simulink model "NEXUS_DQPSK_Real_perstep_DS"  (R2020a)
settings: Solver=VariableStepAuto  StartTime=0.0  StopTime=inf  RelTol=1e-3  EnableMultiTasking=on
InitFcn:
  | FrameSize = 32+1784+256;
  | SamplingTime = 1/(38.4e3)*2;
  | IQframeSize = (32+1784+256)/2;
  | %同期コードが必ず含まれるように32を足す
  | h_time = 1;
  | 
  | % General simulation parameters
  | M = 4;                         % M-PSK alphabet size
  | Upsampling = 4;            % Upsampling factor
  | Downsampling = 2;        % Downsampling factor
  | Fs = 2e6;                     % Sample rate
  | Ts = 1/Fs;                    % Sample time
  | %%FrameSize = 111;          % Number of modulated symbols per frame
  | %MessageLength = 105;  % Number of message bits per frame, 7 ASCII characters
  | BarkerLength = 13;        % Number of Barker code symbols
  | 
  | % TED
  | %fs = 2.4e6;
  | %fs = Fs/2;
  | fs = Fs;
  | Rdata = 100e3;
  | Rsymbol = Rdata/2;
  | 
  | % --- Early Late Timing Synchronisation ----
  | % synch loop design
  | d = 0.707;                   % damping ratio
  | 
  | %Ts = 1/Rsymbol;           % symbol period
  | Ks = 3.22;                    % phase detector coefficient
  | BnS = 0.1*Rsymbol;      % noise bandwidth in Hz
  | Kn   = 1;                      % gain of numerically controlled clock
  | 
  | % calculate loop filter coefficients
  | Ka = (4*d*BnS*Ts)/(Kn*Ks*(d+1/(4*d)));
  | Kb = (4*(BnS*Ts)^2)/(Kn*Ks*(d+1/4*d)^2);
  | 
  | temp=[-1+1i; -1i; -1-1i; -1; 1+1i; 1i; 1-1i; -1; 1+1i; -1i; -1+1i; -1; -1-1i; 1; -1-1i; 1];
  | DQPSKPreamble=temp./abs(temp);
  | PreambleDetectorThreshhold=20;
  | PreambleLength=16;
undefined symbols (not defined in the file or in its folder): Column, D, vector
libraries: dspindex x3, commrfcorlib x2, commsync2 x2, commdigbbndpm3 x1, commfilt2 x1

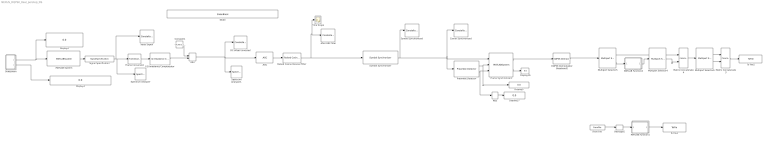
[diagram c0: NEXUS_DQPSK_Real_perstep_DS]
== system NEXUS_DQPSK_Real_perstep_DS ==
  AGC : commrfcorlib/AGC  LegacyMode=off  DetectorMethod=Rectifier  LoopMethod=Linear  UpdatePeriod=100  StepSize=0.1  AdaptationStepSize=0.1  DesiredOutputPower=0.3  AveragingLength=1000  MaximumGain=30  MaxPowerGain=50  GainOutputPort=off  InputPowerOutputPort=off  SimulateUsing=Interpreted execution
  Add : Sum
  After RRC filter : ConstellationDiagram  Commented=on
  Carrier Synchronized : ConstellationDiagram
  Constant1 : Constant  Value=-10.78e-3-10.00e-3j
  DC offset corrected : ConstellationDiagram  Commented=on
  DQPSK Demodulator Baseband2 : commdigbbndpm3/DQPSK Demodulator Baseband  OutType=Bit  Dec=Gray  Ph=pi/4  outDtype1=double  outDtype2=Inherit via internal rule
  Display{2,4..5,16..17} (5 alike) : Display
  Frame Conversion : FrameConversion
  Frame Synchronizer1 : MATLABSystem  System=comm.internal.examples.FrameSynchronizer  Input=Symbol  OutputFrameLength=IQframeSize  PreambleLength=PreambleLength  SimulateUsing=Code generation
  From File : FromFile  Commented=on  SampleTime=0
  I/Q Imbalance Compensator : commrfcorlib/I//Q Imbalance Compensator  Commented=through  CoefficientSource=Estimated from input signal  InitialCoefficient=0 + 0j  StepSizeSource=Property  StepSize=0.00001  AdaptInputPort=off  CoefficientOutputPort=off  SimulateUsing=Code generation
  Input Signal : ConstellationDiagram  Commented=on
  MATLAB Function1 : MATLAB Function  Commented=on  TreatAsAtomicUnit=on
  MATLAB Function4 : MATLAB Function  TreatAsAtomicUnit=on
  MATLAB System : MATLABSystem  System=bladeRF_Simulink_new2  loopback_mode=None  xb200=off  SimulateUsing=Interpreted execution  enable_rx=on  enable_overrun=off  rx_frequency=435.9e6  rx_samplerate=40/SamplingTime  rx_bandwidth=1.5  rx_gain=29  rx_agc=MANUAL  rx_num_buffers=1024  rx_num_transfers=16  rx_buf_size=524288  rx_timeout_ms=15000  rx_step_size=IQframeSize*40  enable_tx=off  enable_underrun=off  tx_frequency=920e6  tx_samplerate=3e6  tx_bandwidth=1.5  tx_gain=60  tx_num_buffers=64  tx_num_transfers=16  tx_buf_size=16384  tx_timeout_ms=5000  tx_step_size=16384  verbosity=Info
  Matrix Concatenate3 : Concatenate  Mode=Multidimensional array
  Matrix Concatenate4 : Concatenate  Mode=Multidimensional array
  Max : MinMax  Function=max
  Multiport Selector4 : dspindex/Multiport Selector  rowsOrCols=Rows  idxCellArray={[1:2040]}  idxErrMode=Clip Index
  Multiport Selector5 : dspindex/Multiport Selector  rowsOrCols=Rows  idxCellArray={[1:32],[33:2072]}  idxErrMode=Clip Index
  Multiport Selector6 : dspindex/Multiport Selector  rowsOrCols=Rows  idxCellArray={[1:1816],[1817:2072]}  idxErrMode=Clip Index
  Preamble Detector : commsync2/Preamble Detector  Input=Symbol  Preamble=DQPSKPreamble  Threshold=7.5  DetectionMetricOutput=on  Detections=First  SimulateUsing=Code generation
  Raised Cosine Receive Filter : commfilt2/Raised Cosine Receive Filter  filtType=Square root  R=0.5  filtSpan=20  N=40  downFactor=10  downOffset=0  filterGain=1/5  InputProcessing=Columns as channels (frame based)  RateOptions=Enforce single-rate processing  framing=Mute  checkCoeff=off  variableName=rcRxFilt  currentFiltSpan=20  D=(20)/2  inputOffset=0  sampMode=Mute  saveAsFlag=0  rateMode=Downsampling  checkGain=Normalized  launchFVT=on  roundingMode=Floor  overflowMode=off  coeffDataTypeStr=Inherit: Same word length as input  coeffMin=[]  coeffMax=[]  coeffLastDataTypeStr=Inherit: Same word length as input  accumDataTypeStr=Inherit: Same as product output  accumLastDataTypeStr=Inherit: Same as product output  outputDataTypeStr=Inherit: Same as accumulator  outputMin=[]  outputMax=[]  outputLastDataTypeStr=Inherit: Same as accumulator
  Reshape5 : Reshape  Commented=on  OutputDimensionality=Column vector (2-D)
  Signal Specification : SignalSpecification  SampleTime=(IQframeSize*400)/(400/SamplingTime)
  Slider : SliderBlock  ScaleMin=-1  ScaleMax=1  TickInterval=0.050000000000000003
  Spectrum Analyzer : SpectrumAnalyzer  Commented=on
  Spectrum Analyzer1 : SpectrumAnalyzer  Commented=on
  Subsystem : Subsystem
  Symbol Synchronized : ConstellationDiagram  Commented=on
  Symbol Synchronizer : commsync2/Symbol Synchronizer  Modulation=PAM/PSK/QAM  TimingErrorDetector=Gardner (non-data-aided)  SamplesPerSymbol=4  DampingFactor=0.86  NormalizedLoopBandwidth=0.0045  DetectorGain=2.7  TimingErrorOutputPort=off  SimulateUsing=Code generation
  Time Scope : Scope
  To File1 : ToFile  Commented=on  Filename=descramble_data
  To File2 : ToFile  Filename=C:\Users\Eve\Desktop\sample_code_Simulink\data_analysis\QPSK_decodedata.mat
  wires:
  Signal Specification/1 -> Spectrum Analyzer/1, Frame Conversion/1, Input Signal/1
  MATLAB System/1 -> Signal Specification/1
  Subsystem/2(Out2) -> Display4/1
  Subsystem/1(Out1) -> MATLAB System/1, Display2/1
  Raised Cosine Receive Filter/1 -> Symbol Synchronizer/1, Time Scope/1, After RRC filter/1
  I/Q Imbalance Compensator/1 -> Add/2
  AGC/1 -> Raised Cosine Receive Filter/1
  Frame Conversion/1 -> I/Q Imbalance Compensator/1
  Add/1 -> Spectrum Analyzer1/1, DC offset corrected/1, AGC/1
  Constant1/1 -> Add/1
  Multiport Selector4/1 -> Matrix Concatenate4/2
  Multiport Selector5/1 -> Matrix Concatenate4/1
  Matrix Concatenate3/1 -> To File2/1
  MATLAB Function4/1(y) -> Multiport Selector4/1
  Multiport Selector6/2 -> Matrix Concatenate3/2
  DQPSK Demodulator Baseband2/1 -> Multiport Selector5/1
  Multiport Selector5/2 -> MATLAB Function4/1(u)
  Matrix Concatenate4/1 -> Multiport Selector6/1
  Multiport Selector6/1 -> Matrix Concatenate3/1
  Max/1 -> Display17/1
  Preamble Detector/1 -> Frame Synchronizer1/2, Display5/1
  Frame Synchronizer1/1 -> DQPSK Demodulator Baseband2/1
  Symbol Synchronizer/1 -> Frame Synchronizer1/1, Carrier Synchronized/1, Preamble Detector/1, Symbol Synchronized/1
  Frame Synchronizer1/2 -> Display16/1
  Preamble Detector/2 -> Frame Synchronizer1/3, Max/1
  Reshape5/1 -> MATLAB Function1/1(u)
  MATLAB Function1/1(y) -> To File1/1
  From File/1 -> Reshape5/1

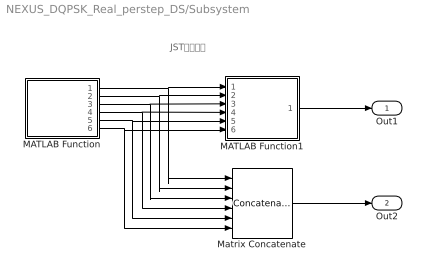
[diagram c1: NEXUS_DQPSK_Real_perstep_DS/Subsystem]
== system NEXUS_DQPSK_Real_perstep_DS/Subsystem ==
  note: JSTのみ対応
  MATLAB Function : MATLAB Function  TreatAsAtomicUnit=on
  MATLAB Function1 : MATLAB Function  TreatAsAtomicUnit=on
  Matrix Concatenate : Concatenate  Commented=on  NumInputs=6  Mode=Multidimensional array  ConcatenateDimension=2
  Out1 : Outport  VectorParamsAs1DForOutWhenUnconnected=off
  Out2 : Outport  Port=2  VectorParamsAs1DForOutWhenUnconnected=off
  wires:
  MATLAB Function/4(H) -> Matrix Concatenate/4, MATLAB Function1/4(H)
  MATLAB Function/3(D) -> Matrix Concatenate/3, MATLAB Function1/3(D)
  MATLAB Function/1(Y) -> Matrix Concatenate/1, MATLAB Function1/1(Y)
  MATLAB Function/5(MN) -> Matrix Concatenate/5, MATLAB Function1/5(MN)
  MATLAB Function/2(M) -> Matrix Concatenate/2, MATLAB Function1/2(M)
  MATLAB Function/6(S) -> Matrix Concatenate/6, MATLAB Function1/6(S)
  MATLAB Function1/1(data) -> Out1/1
  Matrix Concatenate/1 -> Out2/1

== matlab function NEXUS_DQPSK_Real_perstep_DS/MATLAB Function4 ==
function y = fcn(u)

randomiz = [1 1 1 1 1 1 1 1 0 1 0 0 1 0 0 0 0 0 0 0 1 1 1 0 1 1 0 0 0 0 0 0 1 0 0 1 1 0 1 0 0 0 0 0 1 1 0 1 0 1 1 1 0 0 0 0 1 0 1 1 1 1 0 0 1 0 0 0 1 1 1 0 0 0 1 0 1 1 0 0 1 0 0 1 0 0 1 1 1 0 1 0 1 1 0 1 1 0 1 0 0 1 1 1 1 0 1 1 0 1 1 1 0 1 0 0 0 1 1 0 1 1 0 0 1 1 1 0 0 1 0 1 1 0 1 0 1 0 0 1 0 1 1 1 0 1 1 1 1 1 0 1 1 1 0 0 1 1 0 0 0 0 1 1 0 0 1 0 1 0 1 0 0 0 1 0 1 0 1 1 1 1 1 1 0 0 1 1 1 1 1 0 0 0 0 0 1 0 1 0 0 0 0 1 0 0 0 0 1 1 1 1 0 0 0 1 1 0 0 0 1 0 0 0 1 0 0 1 0 1 0 0 1 1 0 0 1 1 0 1 1 1 1 0 1 0 1 0 1 0 1 1 0 0 0 1 1 1 1 1 1 1 1 0 1 0 0 1 0 0 0 0 0 0 0 1 1 1 0 1 1 0 0 0 0 0 0 1 0 0 1 1 0 1 0 0 0 0 0 1 1 0 1 0 1 1 1 0 0 0 0 1 0 1 1 1 1 0 0 1 0 0 0 1 1 1 0 0 0 1 0 1 1 0 0 1 0 0 1 0 0 1 1 1 0 1 0 1 1 0 1 1 0 1 0 0 1 1 1 1 0 1 1 0 1 1 1 0 1 0 0 0 1 1 0 1 1 0 0 1 1 1 0 0 1 0 1 1 0 1 0 1 0 0 1 0 1 1 1 0 1 1 1 1 1 0 1 1 1 0 0 1 1 0 0 0 0 1 1 0 0 1 0 1 0 1 0 0 0 1 0 1 0 1 1 1 1 1 1 0 0 1 1 1 1 1 0 0 0 0 0 1 0 1 0 0 0 0 1 0 0 0 0 1 1 1 1 0 0 0 1 1 0 0 0 1 0 0 0 1 0 0 1 0 1 0 0 1 1 0 0 1 1 0 1 1 1 1 0 1 0 1 0 1 0 1 1 0 0 0 1 1 1 1 1 1 1 1 0 1 0 0 1 0 0 0 0 0 0 0 1 1 1 0 1 1 0 0 0 0 0 0 1 0 0 1 1 0 1 0 0 0 0 0 1 1 0 1 0 1 1 1 0 0 0 0 1 0 1 1 1 1 0 0 1 0 0 0 1 1 1 0 0 0 1 0 1 1 0 0 1 0 0 1 0 0 1 1 1 0 1 0 1 1 0 1 1 0 1 0 0 1 1 1 1 0 1 1 0 1 1 1 0 1 0 0 0 1 1 0 1 1 0 0 1 1 1 0 0 1 0 1 1 0 1 0 1 0 0 1 0 1 1 1 0 1 1 1 1 1 0 1 1 1 0 0 1 1 0 0 0 0 1 1 0 0 1 0 1 0 1 0 0 0 1 0 1 0 1 1 1 1 1 1 0 0 1 1 1 1 1 0 0 0 0 0 1 0 1 0 0 0 0 1 0 0 0 0 1 1 1 1 0 0 0 1 1 0 0 0 1 0 0 0 1 0 0 1 0 1 0 0 1 1 0 0 1 1 0 1 1 1 1 0 1 0 1 0 1 0 1 1 0 0 0 1 1 1 1 1 1 1 1 0 1 0 0 1 0 0 0 0 0 0 0 1 1 1 0 1 1 0 0 0 0 0 0 1 0 0 1 1 0 1 0 0 0 0 0 1 1 0 1 0 1 1 1 0 0 0 0 1 0 1 1 1 1 0 0 1 0 0 0 1 1 1 0 0 0 1 0 1 1 0 0 1 0 0 1 0 0 1 1 1 0 1 0 1 1 0 1 1 0 1 0 0 1 1 1 1 0 1 1 0 1 1 1 0 1 0 0 0 1 1 0 1 1 0 0 1 1 1 0 0 1 0 1 1 0 1 0 1 0 0 1 0 1 1 1 0 1 1 1 1 1 0 1 1 1 0 0 1 1 0 0 0 0 1 1 0 0 1 0 1 0 1 0 0 0 1 0 1 0 1 1 1 1 1 1 0 0 1 1 1 1 1 0 0 0 0 0 1 0 1 0 0 0 0 1 0 0 0 0 1 1 1 1 0 0 0 1 1 0 0 0 1 0 0 0 1 0 0 1 0 1 0 0 1 1 0 0 1 1 0 1 1 1 1 0 1 0 1 0 1 0 1 1 0 0 0 1 1 1 1 1 1 1 1 0 1 0 0 1 0 0 0 0 0 0 0 1 1 1 0 1 1 0 0 0 0 0 0 1 0 0 1 1 0 1 0 0 0 0 0 1 1 0 1 0 1 1 1 0 0 0 0 1 0 1 1 1 1 0 0 1 0 0 0 1 1 1 0 0 0 1 0 1 1 0 0 1 0 0 1 0 0 1 1 1 0 1 0 1 1 0 1 1 0 1 0 0 1 1 1 1 0 1 1 0 1 1 1 0 1 0 0 0 1 1 0 1 1 0 0 1 1 1 0 0 1 0 1 1 0 1 0 1 0 0 1 0 1 1 1 0 1 1 1 1 1 0 1 1 1 0 0 1 1 0 0 0 0 1 1 0 0 1 0 1 0 1 0 0 0 1 0 1 0 1 1 1 1 1 1 0 0 1 1 1 1 1 0 0 0 0 0 1 0 1 0 0 0 0 1 0 0 0 0 1 1 1 1 0 0 0 1 1 0 0 0 1 0 0 0 1 0 0 1 0 1 0 0 1 1 0 0 1 1 0 1 1 1 1 0 1 0 1 0 1 0 1 1 0 0 0 1 1 1 1 1 1 1 1 0 1 0 0 1 0 0 0 0 0 0 0 1 1 1 0 1 1 0 0 0 0 0 0 1 0 0 1 1 0 1 0 0 0 0 0 1 1 0 1 0 1 1 1 0 0 0 0 1 0 1 1 1 1 0 0 1 0 0 0 1 1 1 0 0 0 1 0 1 1 0 0 1 0 0 1 0 0 1 1 1 0 1 0 1 1 0 1 1 0 1 0 0 1 1 1 1 0 1 1 0 1 1 1 0 1 0 0 0 1 1 0 1 1 0 0 1 1 1 0 0 1 0 1 1 0 1 0 1 0 0 1 0 1 1 1 0 1 1 1 1 1 0 1 1 1 0 0 1 1 0 0 0 0 1 1 0 0 1 0 1 0 1 0 0 0 1 0 1 0 1 1 1 1 1 1 0 0 1 1 1 1 1 0 0 0 0 0 1 0 1 0 0 0 0 1 0 0 0 0 1 1 1 1 0 0 0 1 1 0 0 0 1 0 0 0 1 0 0 1 0 1 0 0 1 1 0 0 1 1 0 1 1 1 1 0 1 0 1 0 1 0 1 1 0 0 0 1 1 1 1 1 1 1 1 0 1 0 0 1 0 0 0 0 0 0 0 1 1 1 0 1 1 0 0 0 0 0 0 1 0 0 1 1 0 1 0 0 0 0 0 1 1 0 1 0 1 1 1 0 0 0 0 1 0 1 1 1 1 0 0 1 0 0 0 1 1 1 0 0 0 1 0 1 1 0 0 1 0 0 1 0 0 1 1 1 0 1 0 1 1 0 1 1 0 1 0 0 1 1 1 1 0 1 1 0 1 1 1 0 1 0 0 0 1 1 0 1 1 0 0 1 1 1 0 0 1 0 1 1 0 1 0 1 0 0 1 0 1 1 1 0 1 1 1 1 1 0 1 1 1 0 0 1 1 0 0 0 0 1 1 0 0 1 0 1 0 1 0 0 0 1 0 1 0 1 1 1 1 1 1 0 0 1 1 1 1 1 0 0 0 0 0 1 0 1 0 0 0 0 1 0 0 0 0 1 1 1 1 0 0 0 1 1 0 0 0 1 0 0 0 1 0 0 1 0 1 0 0 1 1 0 0 1 1 0 1 1 1 1 0 1 0 1 0 1 0 1 1 0 0 0 1 1 1 1 1 1 1 1 0 1 0 0 1 0 0 0 0 0 0 0 1 1 1 0 1 1 0 0 0 0 0 0 1 0 0 1 1 0 1 0 0 0 0 0 1 1 0 1 0 1 1 1 0 0 0 0 1 0 1 1 1 1 0 0 1 0 0 0 1 1 1 0 0 0 1 0 1 1 0 0 1 0 0 1 0 0 1 1 1 0 1 0 1 1 0 1 1 0 1 0 0 1 1 1 1 0 1 1 0 1 1 1 0 1 0 0 0 1 1 0 1 1 0 0 1 1 1 0 0 1 0 1 1 0 1 0 1 0 0 1 0 1 1 1 0 1 1 1 1 1 0 1 1 1 0 0 1 1 0 0 0 0 1 1 0 0 1 0 1 0 1 0 0 0 1 0 1 0 1 1 1 1 1 1 0 0 1 1 1 1 1 0 0 0 0 0 1 0 1 0 0 0 0 1 0 0 0 0 1 1 1 1 0 0 0 1 1 0 0 0 1 0 0 0 1 0 0 1 0 1 0 0 1 1 0 0 1 1 0 1 1 1 1 0 1 0 1 0 1 0 1 1 0 0 0]';
y = bitxor(randomiz,u);

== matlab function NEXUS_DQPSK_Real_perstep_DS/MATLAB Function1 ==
function y = fcn(u)

randomiz = [1 1 1 1 1 1 1 1 0 1 0 0 1 0 0 0 0 0 0 0 1 1 1 0 1 1 0 0 0 0 0 0 1 0 0 1 1 0 1 0 0 0 0 0 1 1 0 1 0 1 1 1 0 0 0 0 1 0 1 1 1 1 0 0 1 0 0 0 1 1 1 0 0 0 1 0 1 1 0 0 1 0 0 1 0 0 1 1 1 0 1 0 1 1 0 1 1 0 1 0 0 1 1 1 1 0 1 1 0 1 1 1 0 1 0 0 0 1 1 0 1 1 0 0 1 1 1 0 0 1 0 1 1 0 1 0 1 0 0 1 0 1 1 1 0 1 1 1 1 1 0 1 1 1 0 0 1 1 0 0 0 0 1 1 0 0 1 0 1 0 1 0 0 0 1 0 1 0 1 1 1 1 1 1 0 0 1 1 1 1 1 0 0 0 0 0 1 0 1 0 0 0 0 1 0 0 0 0 1 1 1 1 0 0 0 1 1 0 0 0 1 0 0 0 1 0 0 1 0 1 0 0 1 1 0 0 1 1 0 1 1 1 1 0 1 0 1 0 1 0 1 1 0 0 0 1 1 1 1 1 1 1 1 0 1 0 0 1 0 0 0 0 0 0 0 1 1 1 0 1 1 0 0 0 0 0 0 1 0 0 1 1 0 1 0 0 0 0 0 1 1 0 1 0 1 1 1 0 0 0 0 1 0 1 1 1 1 0 0 1 0 0 0 1 1 1 0 0 0 1 0 1 1 0 0 1 0 0 1 0 0 1 1 1 0 1 0 1 1 0 1 1 0 1 0 0 1 1 1 1 0 1 1 0 1 1 1 0 1 0 0 0 1 1 0 1 1 0 0 1 1 1 0 0 1 0 1 1 0 1 0 1 0 0 1 0 1 1 1 0 1 1 1 1 1 0 1 1 1 0 0 1 1 0 0 0 0 1 1 0 0 1 0 1 0 1 0 0 0 1 0 1 0 1 1 1 1 1 1 0 0 1 1 1 1 1 0 0 0 0 0 1 0 1 0 0 0 0 1 0 0 0 0 1 1 1 1 0 0 0 1 1 0 0 0 1 0 0 0 1 0 0 1 0 1 0 0 1 1 0 0 1 1 0 1 1 1 1 0 1 0 1 0 1 0 1 1 0 0 0 1 1 1 1 1 1 1 1 0 1 0 0 1 0 0 0 0 0 0 0 1 1 1 0 1 1 0 0 0 0 0 0 1 0 0 1 1 0 1 0 0 0 0 0 1 1 0 1 0 1 1 1 0 0 0 0 1 0 1 1 1 1 0 0 1 0 0 0 1 1 1 0 0 0 1 0 1 1 0 0 1 0 0 1 0 0 1 1 1 0 1 0 1 1 0 1 1 0 1 0 0 1 1 1 1 0 1 1 0 1 1 1 0 1 0 0 0 1 1 0 1 1 0 0 1 1 1 0 0 1 0 1 1 0 1 0 1 0 0 1 0 1 1 1 0 1 1 1 1 1 0 1 1 1 0 0 1 1 0 0 0 0 1 1 0 0 1 0 1 0 1 0 0 0 1 0 1 0 1 1 1 1 1 1 0 0 1 1 1 1 1 0 0 0 0 0 1 0 1 0 0 0 0 1 0 0 0 0 1 1 1 1 0 0 0 1 1 0 0 0 1 0 0 0 1 0 0 1 0 1 0 0 1 1 0 0 1 1 0 1 1 1 1 0 1 0 1 0 1 0 1 1 0 0 0 1 1 1 1 1 1 1 1 0 1 0 0 1 0 0 0 0 0 0 0 1 1 1 0 1 1 0 0 0 0 0 0 1 0 0 1 1 0 1 0 0 0 0 0 1 1 0 1 0 1 1 1 0 0 0 0 1 0 1 1 1 1 0 0 1 0 0 0 1 1 1 0 0 0 1 0 1 1 0 0 1 0 0 1 0 0 1 1 1 0 1 0 1 1 0 1 1 0 1 0 0 1 1 1 1 0 1 1 0 1 1 1 0 1 0 0 0 1 1 0 1 1 0 0 1 1 1 0 0 1 0 1 1 0 1 0 1 0 0 1 0 1 1 1 0 1 1 1 1 1 0 1 1 1 0 0 1 1 0 0 0 0 1 1 0 0 1 0 1 0 1 0 0 0 1 0 1 0 1 1 1 1 1 1 0 0 1 1 1 1 1 0 0 0 0 0 1 0 1 0 0 0 0 1 0 0 0 0 1 1 1 1 0 0 0 1 1 0 0 0 1 0 0 0 1 0 0 1 0 1 0 0 1 1 0 0 1 1 0 1 1 1 1 0 1 0 1 0 1 0 1 1 0 0 0 1 1 1 1 1 1 1 1 0 1 0 0 1 0 0 0 0 0 0 0 1 1 1 0 1 1 0 0 0 0 0 0 1 0 0 1 1 0 1 0 0 0 0 0 1 1 0 1 0 1 1 1 0 0 0 0 1 0 1 1 1 1 0 0 1 0 0 0 1 1 1 0 0 0 1 0 1 1 0 0 1 0 0 1 0 0 1 1 1 0 1 0 1 1 0 1 1 0 1 0 0 1 1 1 1 0 1 1 0 1 1 1 0 1 0 0 0 1 1 0 1 1 0 0 1 1 1 0 0 1 0 1 1 0 1 0 1 0 0 1 0 1 1 1 0 1 1 1 1 1 0 1 1 1 0 0 1 1 0 0 0 0 1 1 0 0 1 0 1 0 1 0 0 0 1 0 1 0 1 1 1 1 1 1 0 0 1 1 1 1 1 0 0 0 0 0 1 0 1 0 0 0 0 1 0 0 0 0 1 1 1 1 0 0 0 1 1 0 0 0 1 0 0 0 1 0 0 1 0 1 0 0 1 1 0 0 1 1 0 1 1 1 1 0 1 0 1 0 1 0 1 1 0 0 0 1 1 1 1 1 1 1 1 0 1 0 0 1 0 0 0 0 0 0 0 1 1 1 0 1 1 0 0 0 0 0 0 1 0 0 1 1 0 1 0 0 0 0 0 1 1 0 1 0 1 1 1 0 0 0 0 1 0 1 1 1 1 0 0 1 0 0 0 1 1 1 0 0 0 1 0 1 1 0 0 1 0 0 1 0 0 1 1 1 0 1 0 1 1 0 1 1 0 1 0 0 1 1 1 1 0 1 1 0 1 1 1 0 1 0 0 0 1 1 0 1 1 0 0 1 1 1 0 0 1 0 1 1 0 1 0 1 0 0 1 0 1 1 1 0 1 1 1 1 1 0 1 1 1 0 0 1 1 0 0 0 0 1 1 0 0 1 0 1 0 1 0 0 0 1 0 1 0 1 1 1 1 1 1 0 0 1 1 1 1 1 0 0 0 0 0 1 0 1 0 0 0 0 1 0 0 0 0 1 1 1 1 0 0 0 1 1 0 0 0 1 0 0 0 1 0 0 1 0 1 0 0 1 1 0 0 1 1 0 1 1 1 1 0 1 0 1 0 1 0 1 1 0 0 0 1 1 1 1 1 1 1 1 0 1 0 0 1 0 0 0 0 0 0 0 1 1 1 0 1 1 0 0 0 0 0 0 1 0 0 1 1 0 1 0 0 0 0 0 1 1 0 1 0 1 1 1 0 0 0 0 1 0 1 1 1 1 0 0 1 0 0 0 1 1 1 0 0 0 1 0 1 1 0 0 1 0 0 1 0 0 1 1 1 0 1 0 1 1 0 1 1 0 1 0 0 1 1 1 1 0 1 1 0 1 1 1 0 1 0 0 0 1 1 0 1 1 0 0 1 1 1 0 0 1 0 1 1 0 1 0 1 0 0 1 0 1 1 1 0 1 1 1 1 1 0 1 1 1 0 0 1 1 0 0 0 0 1 1 0 0 1 0 1 0 1 0 0 0 1 0 1 0 1 1 1 1 1 1 0 0 1 1 1 1 1 0 0 0 0 0 1 0 1 0 0 0 0 1 0 0 0 0 1 1 1 1 0 0 0 1 1 0 0 0 1 0 0 0 1 0 0 1 0 1 0 0 1 1 0 0 1 1 0 1 1 1 1 0 1 0 1 0 1 0 1 1 0 0 0 1 1 1 1 1 1 1 1 0 1 0 0 1 0 0 0 0 0 0 0 1 1 1 0 1 1 0 0 0 0 0 0 1 0 0 1 1 0 1 0 0 0 0 0 1 1 0 1 0 1 1 1 0 0 0 0 1 0 1 1 1 1 0 0 1 0 0 0 1 1 1 0 0 0 1 0 1 1 0 0 1 0 0 1 0 0 1 1 1 0 1 0 1 1 0 1 1 0 1 0 0 1 1 1 1 0 1 1 0 1 1 1 0 1 0 0 0 1 1 0 1 1 0 0 1 1 1 0 0 1 0 1 1 0 1 0 1 0 0 1 0 1 1 1 0 1 1 1 1 1 0 1 1 1 0 0 1 1 0 0 0 0 1 1 0 0 1 0 1 0 1 0 0 0 1 0 1 0 1 1 1 1 1 1 0 0 1 1 1 1 1 0 0 0 0 0 1 0 1 0 0 0 0 1 0 0 0 0 1 1 1 1 0 0 0 1 1 0 0 0 1 0 0 0 1 0 0 1 0 1 0 0 1 1 0 0 1 1 0 1 1 1 1 0 1 0 1 0 1 0 1 1 0 0 0]';
y = bitxor(randomiz,u);

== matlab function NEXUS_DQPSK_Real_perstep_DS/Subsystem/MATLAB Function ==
function [Y, M, D, H, MN, S] = fcn()
   eml.extrinsic('now');
   eml.extrinsic('datevec');
   Y = 0;
   M = 0;
   D = 0;
   H = 0;
   MN = 0;
   S = 0;
   [Y, M, D, H, MN, S] = datevec(now);
end

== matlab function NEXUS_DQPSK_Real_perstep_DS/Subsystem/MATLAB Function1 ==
function data = SGP4(Y,M,D,H,MN,S)

%% ---- Description ---- %%
% SGP4による軌道計算
% out_vgに地上局から見た衛星の速度を格納
% ↑x,y,z,normで格納

%% ---- Code ----- %%
%%% 現在時間の取得%%%%%%%%%%%%%%%%%%%%%%%%%%%%%%%%%%%%%%%%%%%%%%%%%%%%%%%%%
%%% test time %%%%%%%%%
% year   = 2019;
% month  = 1;
% day    = 13;
% hour   = 23;
% minute = 51;
% second = 0;
% time_difference = -9;
%%%%%%%%%%%%%%%%%%%%%%%

%=======TLE Update tool貼り付け=======

year0=2021;
D0=18.1025;
Bstar=5.6579e-05;
i0=1.6964;
OMEGA0=1.1726;
e0=0.0023553;
omega0=3.165;
M0=3.1202;
n0=0.066545;

%=======TLE Update tool貼り付け=======


% time = u;
% disp(time);
% year   = time(1,1);
% month  = time(1,2);
% day    = time(1,3);
% hour   = time(1,4);
% minute = time(1,5);
% second = time(1,6);
% year   = 2019;
% month  = 1;
% day    = 22;
% hour   = 2;
% minute = 59;
% second = 0;
time_difference = -9;

%%%%%%%%%%%%%%%%%%%%%%%%%%%%%%%%%%%%%%%%%%%%%%%%%%%%%%%%%%%%%%%%%%%%%%%%%%%

% TLEの読み込み
%[year0,D0,Bstar,i0,e0,OMEGA0,omega0,M0,n0] = TLE_Reader();

% ユリウス日

JD0 = Get_JulianDay(year0, 1.0 , D0, 0.0, 0.0, 0.0 ,0);
JDi = Get_JulianDay(Y, M, D, H, MN, S, time_difference);
JD = JDi;

% SGP4による軌道計算
%%%%%%%%%%%%%%%%%%%%%%%%%%%%%%%%%%%%%%%%%%%%%%%%%%%%%%%%%%%%%
%SGP4中身
%%%%%%%%%%%%%%%%%%%%%%%%%%%%%%%%%%%%%%%%%%%%%%%%%%%%%%%%%%%%%
%% 定数定義
Re_s   = 6378.135; %km
Lref   = 6378.135;
tref   = 60.0;
J2     = 1082.616*10^-6;
J3     = -2.53881*10^-6;
J4     = -1.65597*10^-6;
s0_s   = 78.0;
q0_s   = 120.0;
myue_s = 398600.0;
%% 定数計算
Re_    = Re_s/Lref;
s0     = s0_s/Lref;
s      = Re_+s0;
qs     = ((q0_s-s0_s)/Lref)^4;
myue   = myue_s*(tref^2)/(Lref^3);
k2     = J2*Re_^2/2 ;
k4     = J4*Re_^4*3.0/8.0 ;
ke     = sqrt(myue);
A3_0   = J3*Re_^3;
a1     = (ke/n0)^(2.0/3.0);
c1     = 1.5*k2*(3*cos(i0)^2-1.0)/(1.0-e0*e0^1.5);
delta1 = c1/a1^2.0;
a0     =  a1*(1.0-delta1/3.0-delta1^2.0-134.0/81.0*delta1^3.0);
delta0 = c1/a0^2.0;
n0dd   = n0/(1.0+delta0); %/*mean motion*/
a0dd   = a0/(1.0-delta0); %/*mean radius*/
ci     = cos(i0);
si     = sin(i0);
beta0  = sqrt(1.0-e0^2.0);
gzi    = 1.0/(a0dd-s);
eta    = a0dd*e0*gzi;
c2     = 1.0-eta^2.0;
c3     = qs*gzi^4.0*n0dd*c2^(-7.0/2.0);
c4     = 1.0+1.5*eta^2.0+4.0*e0*eta+e0*eta^3.0;
c5     = k2*gzi/c2;
C2     = c3*(a0dd*c4+1.5*c5*(-0.5+1.5*c1^2.0)*(8.0+24.0*eta^2.0+3.0*eta^4.0));
C1     = Bstar*C2;
C3     = qs*gzi^5.0*A3_0*n0dd*Re_*si/k2/e0;
c6     = 2.0*eta*(1+e0*eta)+e0/2.0+eta^3.0/2.0;
c7     = 2.0*eta^2.0-e0*eta-e0*eta^3.0;
C4     = 2.0*c3*a0dd*beta0^2.0*(c6-2.0*c5/a0dd*(3.0*(1.0-3.0*ci^2.0)*c4+0.75*si^2.0*c7*cos(2.0*omega0)));
C5     = 2.0*c3*a0dd/n0dd*beta0^2.0*(1.0+11.0/4.0*eta*(eta+e0)+e0*eta^3.0);
D2     = 4.0*a0dd*gzi*C1^2.0;
D3     = 4.0*a0dd^2.0*gzi^2.0*C1^3.0*(17.0*a0dd+s)/3.0;
D4     = (2.0*a0dd^2.0*gzi^3.0*C1^4.0*(221.0 *a0dd+31.0*s))/3.0;
% debugJD = (JD)
% debugJD0 = (JD0)
% debug3 = (JD-JD0)
Dt     = 86400*(JD-JD0)/tref;
Dt2    = Dt^2;
Dt3    = Dt^3;
Dt4    = Dt^4;
Dt5    = Dt^5;
%% 5. 第一近似
c1     = 3.0*k2/(a0dd^2.0*beta0^4.0);
c2     = 3.0*k2*k2/(a0dd^4.0*beta0^8.0);
c3     = 5.0*k4/(a0dd^4.0*beta0^8.0);
M1     = M0+(1.0+c1*beta0*(-1.0+3.0*ci^2.0)/2.0+c2*beta0*(13.0-78.0*ci^2.0+137.0*ci^4.0)/16.0)*n0dd*Dt;
omega1 = omega0+(-c1*(1.0-5.0*ci*ci)/2.0+c2*(7.0-114.0*ci*ci+395.0*ci^4.0)/16.0+c3*(3.0-36.0*ci*ci+49.0*ci^4.0)/4.0)*n0dd*Dt;
OMEGA1 = OMEGA0+(-c1*ci+c2*(4.0*ci-19.0*ci^3.0)/2.0+c3*ci*(3.0-7.0*ci*ci)/2.0)*n0dd*Dt;


M1     = trans_radian(M1);
omega1 = trans_radian(omega1);
OMEGA1 = trans_radian(OMEGA1);

%% 6. 第二近似
deltaomega = Bstar*C3*cos(omega0)*Dt;
deltaM     = -2.0*qs*Bstar*gzi^4.0*Re_*((1.0+eta*cos(M1))^3.0-(1.0+eta*cos(M0))^3.0)/(3.0*e0*eta);
M2         = M1+deltaomega+deltaM;
omega2     = omega1-deltaomega-deltaM;
OMEGA2     = OMEGA1-21.0*n0dd*k2*ci*C1*Dt2/(2.0*a0dd*a0dd*beta0*beta0);
a2         = a0dd*(1.0-C1*Dt-D2*Dt2-D3*Dt3-D4*Dt4)*(1.0-C1*Dt-D2*Dt2-D3*Dt3-D4*Dt4);
e2         = e0-Bstar*C4*Dt-Bstar*C5*(sin(M2)-sin(M0));
n2         = ke/a2^1.5;
M2         = trans_radian(M2);
omega2     = trans_radian(omega2);
OMEGA2     = trans_radian(OMEGA2);



%% 7. 第三近似
IL_2       = M2+omega2+OMEGA2+n0dd*(1.5*C1*Dt2+(D2+2.0*C1*C1)*Dt3+(3.0*D3+12.0*C1*D2+10.0*C1*C1*C1)*Dt4/4.0+(3.0*D4+12.0*C1*D3+6.0*D2*D2+30.0*C1*C1*D2+15.0*C1^4.0)*Dt5/5.0);
beta2      = sqrt(1.0-e2*e2);
a_xN       = e2*cos(omega2);
a_yNL      = A3_0*si/(4.0*k2*a2*beta2*beta2);
IL_L       = a_yNL/2.0*a_xN*(3.0+5.0*ci)/(1.0+ci);
IL_T       = IL_2+IL_L;
a_yN       = e2*sin(omega2)+a_yNL;
e3         = sqrt(a_xN*a_xN+a_yN*a_yN);
x3         = omega2+M2;
while(sqrt((-(x3+a_yN*cos(x3)-a_xN*sin(x3)-IL_T+OMEGA2)/...
         (1.0-a_yN*sin(x3)-a_xN*cos(x3)))^2.0)>0.00000001)
    x3 = x3-(x3+a_yN*cos(x3)-a_xN*sin(x3)-IL_T+OMEGA2)/...
         (1.0-a_yN*sin(x3)-a_xN*cos(x3));
end

x3 = trans_radian(x3);
E3 = atan2(a_xN*sin(x3)-a_yN*cos(x3),a_xN*cos(x3)+a_yN*sin(x3));
E3 = trans_radian(E3);
r3 = a2*(1.0 - e3*cos(E3));
v3 = ke*sqrt(a2)/r3*e3*sin(E3);
p3 = a2*(1.0- e3*e3);
z3 = ke*sqrt(p3)/r3;
u3 = atan2(sin(x3)-a_yN-a_xN*e3*sin(E3)/(1.0+sqrt(1.0-e3*e3)),cos(x3)-a_xN+a_yN*e3*sin(E3)/(1.0+sqrt(1.0-e3*e3)));
u3 = trans_radian(u3);

%% 8. 軌道要素	
dr  = k2*(1.0-ci*ci)*cos(2.0*u3)/2.0/p3;
r_f = r3*(1.0-1.5*k2*sqrt(1.0-e3*e3)*(3.0*ci*ci-1.0)/p3/p3)+dr;
du  = -0.25*k2*(7.0*ci*ci-1.0)*sin(2.0*u3)/p3/p3;
u_f = u3+du;
u_f = trans_radian(u_f);
dOMEGA  = 1.5*k2*ci*sin(2.0*u3)/p3/p3;
OMEGA_f = OMEGA2+dOMEGA;
OMEGA_f = trans_radian(OMEGA_f);
di      = 1.5*k2*ci*si*cos(2.0*u3)/p3/p3;
i_f     = i0+di;
i_f=trans_radian(i_f);
dv=-k2*n2*si*si*sin(2.0*u3)/p3;
v_f=v3+dv;
dz=k2*n2*(si*si*cos(2.0*u3)-1.5*(1.0-3.0*ci*ci))/p3;
z_f=z3+dz;


%% グリニッジ標準時    
D=D0+Dt/86400.0*tref;
Dg=floor(D);
JDg=Get_JulianDay(year0,1,Dg,0.0,0.0,0.0,0);

Cg= JDg/36525.0 + 1;
%Cg = (JD - 2451544.5) / 36525.0;
Lt=24.0*(JD + 0.5 - floor(JD + 0.5));
psie=2.0*pi/24.0*(6.0+38.0/60.0+45.836/3600.0+8640184.542/3600.0*Cg+0.0929/3600.0*Cg*Cg+Lt*(1.0+1.0/365.2422));
psie=trans_radian(psie);
% pause
%% 衛星の位置、速度 (地球中心赤道面基準座標系 R0）
M =[-sin(OMEGA_f)*cos(i_f);cos(OMEGA_f)*cos(i_f);sin(i_f) ];	
N =[cos(OMEGA_f);sin(OMEGA_f);0];
U = M*sin(u_f)+ N*cos(u_f);
V = M*cos(u_f)- N*sin(u_f);   
x0=r_f*U*Re_s; % 衛星の位置ベクトル [km]
v0=(v_f*U+z_f*V)*Lref/60;   %衛星の速度ベクトル [km/s]
%v0=(v_f*U+z_f*V);


% 絶対座標系（地球中心黄道面基準座標系）RE  

% if (con1>0.0)&&(con2<Re_s)            
%     sunjudge=0;        
% else
%     sunjudge=1;
%     suntime=suntime+1.0; 
% end

%%%%%%%%%%%%%%%%%%%%%%%%%%%%%%%%%%%%%%%%%%%%%%%%%%%%%%%%%%%%%
%SGP4中身
%%%%%%%%%%%%%%%%%%%%%%%%%%%%%%%%%%%%%%%%%%%%%%%%%%%%%%%%%%%%%

% 地上局の経度:lambda_g，緯度:phi_g  (日本大学理工学部船橋校舎3号館)
lambda_g = 140.05688*pi/180; % [rad]
phi_g    = 35.724730*pi/180;    % [rad]
Re_s     = 6378.135;% [km]
gs_hight = 0.050; % [km]
gsre_hight = (Re_s + gs_hight);   % [km]

% 地上局の位置（地球中心）
phi_gs = phi_g;   % [rad]
lambda_gs = lambda_g + psie;       % [rad]

GS_vec = [gsre_hight * cos(phi_gs) * cos(lambda_gs);
          gsre_hight * cos(phi_gs) * sin(lambda_gs);
          gsre_hight * sin(phi_gs)];
      
% 地上局から見た衛星の位置・速度
GS_v_vec = cross ([0 ; 0 ; 2*pi*(1+1/365.2422)/86400],GS_vec); %地球中心地上局の速度ベクトル＝角速度ベクトル×地上局位置ベクトル
satU = x0 - GS_vec; %衛星の位置ベクトル-地上局の位置ベクトル＝地上局から見た衛星の位置ベクトル
satU_0vec = satU/norm(satU); %地上局から見た衛星の位置ベクトルの単位ベクトル
satV = (v0 - GS_v_vec)' * satU_0vec; %km/sec '=内積を取ってる(転置)，結局は速度の大きさ
% ドップラーシフト計算
F0 = 435.900 * 10^6; %Hz
Fd = -F0 * satV / (299792458 + satV);
Fd2 = F0 + Fd * 10^3;
% Fd2 = F0 + Fd * 10^3;
data = Fd2;
% data = F0;


end
